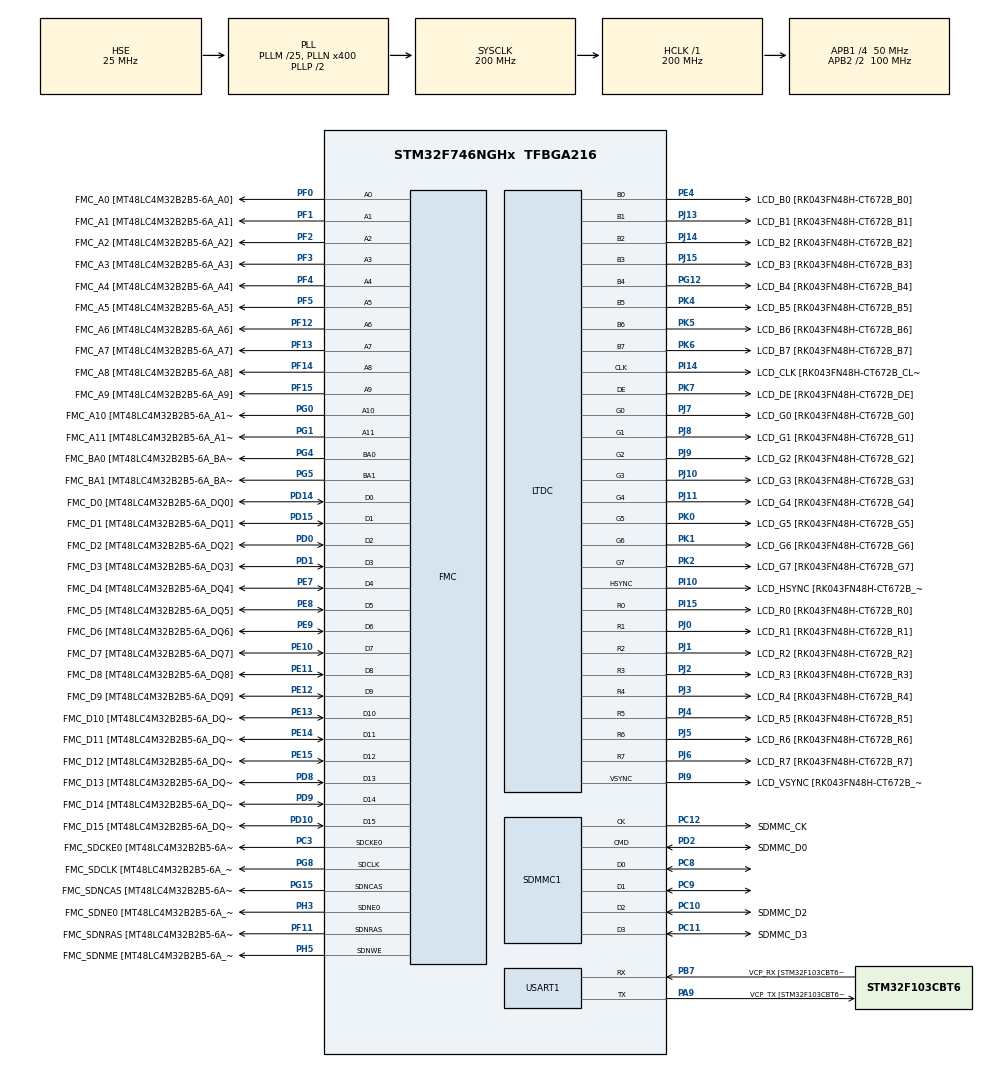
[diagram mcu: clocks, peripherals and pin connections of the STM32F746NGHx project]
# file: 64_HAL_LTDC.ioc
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CORTEX_M7.CPU_DCache=Enabled
CORTEX_M7.CPU_ICache=Enabled
FATFS._MAX_SS=4096
FMC.CASLatency1=FMC_SDRAM_CAS_LATENCY_2
FMC.ExitSelfRefreshDelay1=6
FMC.LoadToActiveDelay1=2
FMC.RCDDelay1=2
FMC.RPDelay1=2
FMC.RPDelay2=2
FMC.RowCycleDelay1=6
FMC.RowCycleDelay2=6
FMC.SelfRefreshTime1=4
FMC.WriteRecoveryTime1=2
FREERTOS.Tasks01=defaultTask,0,1280,StartDefaultTask,Default,NULL,Dynamic,NULL,NULL;myTask02,-3,128,StartTask02,Default,NULL,Dynamic,NULL,NULL;myTask03,-3,128,StartTask03,Default,NULL,Dynamic,NULL,NULL;myTask04,-3,128,StartTask04,Default,NULL,Dynamic,NULL,NULL;myTask05,-3,128,StartTask05,Default,NULL,Dynamic,NULL,NULL
FREERTOS.configUSE_IDLE_HOOK=0
LTDC.ActiveH=272
LTDC.ActiveW=480
LTDC.Alpha_L0=255
LTDC.Alpha_L1=255
LTDC.HBP=13
LTDC.HFP=32
LTDC.HSync=41
LTDC.Layers=0
LTDC.PixelFormat_L0=LTDC_PIXEL_FORMAT_RGB565
LTDC.VSync=10
LTDC.WindowX1_L0=480
LTDC.WindowX1_L1=480
LTDC.WindowY1_L0=272
LTDC.WindowY1_L1=272
Mcu.Family=STM32F7
Mcu.Name=STM32F746NGHx
Mcu.Package=TFBGA216
NVIC.PriorityGroup=NVIC_PRIORITYGROUP_4
NVIC.TIM1_UP_TIM10_IRQn=true\:15\:0\:false\:false\:true\:false\:false\:true
NVIC.TimeBase=TIM1_UP_TIM10_IRQn
NVIC.TimeBaseIP=TIM1
PA13.GPIO_Label=SWDIO
PA13.Mode=Serial_Wire
PA13.Signal=SYS_JTMS-SWDIO
PA14.GPIO_Label=SWCLK
PA14.Mode=Serial_Wire
PA14.Signal=SYS_JTCK-SWCLK
PA15.GPIO_Label=ARDUINO PWM/D9
PA15.GPIO_ModeDefaultPP=GPIO_MODE_AF_PP
PA15.GPIO_PuPd=GPIO_NOPULL
PA15.GPIO_Speed=GPIO_SPEED_FREQ_LOW
PA15.Signal=S_TIM2_CH1_ETR
PA9.GPIO_Label=VCP_TX [STM32F103CBT6_PA3]
PA9.GPIO_Mode=GPIO_MODE_AF_PP
PA9.GPIO_PuPd=GPIO_NOPULL
PA9.GPIO_Speed=GPIO_SPEED_FREQ_LOW
PA9.Mode=Asynchronous
PA9.Signal=USART1_TX
PB0.GPIO_Label=ULPI_D1 [USB3320C-EZK_D1]
PB0.Signal=USB_OTG_HS_ULPI_D1
PB1.GPIO_Label=ULPI_D2 [USB3320C-EZK_D2]
PB1.Signal=USB_OTG_HS_ULPI_D2
PB10.GPIO_Label=ULPI_D3 [USB3320C-EZK_D3]
PB10.Signal=USB_OTG_HS_ULPI_D3
PB11.GPIO_Label=ULPI_D4 [USB3320C-EZK_D4]
PB11.Signal=USB_OTG_HS_ULPI_D4
PB12.GPIO_Label=ULPI_D5 [USB3320C-EZK_D5]
PB12.Signal=USB_OTG_HS_ULPI_D5
PB13.GPIO_Label=ULPI_D6 [USB3320C-EZK_D6]
PB13.Signal=USB_OTG_HS_ULPI_D6
PB14.GPIO_Label=ARDUINO MISO/D12
PB14.GPIO_Mode=GPIO_MODE_AF_PP
PB14.GPIO_PuPd=GPIO_NOPULL
PB14.GPIO_Speed=GPIO_SPEED_FREQ_LOW
PB14.Signal=SPI2_MISO
PB15.GPIO_Label=ARDUINO MOSI/PWM/D11
PB15.GPIO_Mode=GPIO_MODE_AF_PP
PB15.GPIO_PuPd=GPIO_NOPULL
PB15.GPIO_Speed=GPIO_SPEED_FREQ_LOW
PB15.Signal=SPI2_MOSI
PB2.Signal=QUADSPI_CLK
PB3.GPIO_Label=SWO
PB3.Signal=SYS_JTDO-SWO
PB4.GPIO_Label=ARDUINO PWM/D3
PB4.GPIO_ModeDefaultPP=GPIO_MODE_AF_PP
PB4.GPIO_PuPd=GPIO_NOPULL
PB4.GPIO_Speed=GPIO_SPEED_FREQ_LOW
PB4.Signal=S_TIM3_CH1
PB5.GPIO_Label=ULPI_D7 [USB3320C-EZK_D7]
PB5.Signal=USB_OTG_HS_ULPI_D7
PB6.GPIO_Label=QSPI_NCS [N25Q128A13EF840E_S]
PB6.Signal=QUADSPI_BK1_NCS
PB7.GPIO_Label=VCP_RX [STM32F103CBT6_PA2]
PB7.GPIO_Mode=GPIO_MODE_AF_PP
PB7.GPIO_PuPd=GPIO_NOPULL
PB7.GPIO_Speed=GPIO_SPEED_FREQ_LOW
PB7.Mode=Asynchronous
PB7.Signal=USART1_RX
PB8.GPIO_Label=ARDUINO SCL/D15
PB8.GPIO_Mode=GPIO_MODE_AF_OD
PB8.GPIO_PuPd=GPIO_NOPULL
PB8.GPIO_Speed=GPIO_SPEED_FREQ_LOW
PB8.Signal=I2C1_SCL
PB9.GPIO_Label=ARDUINO SDA/D14
PB9.GPIO_Mode=GPIO_MODE_AF_OD
PB9.GPIO_PuPd=GPIO_NOPULL
PB9.GPIO_Speed=GPIO_SPEED_FREQ_LOW
PB9.Signal=I2C1_SDA
PC1.GPIO_Label=RMII_MDC [LAN8742A-CZ-TR_MDC]
PC1.Signal=ETH_MDC
PC10.GPIO_Label=SDMMC_D2
PC10.Mode=SD_4_bits_Wide_bus
PC10.Signal=SDMMC1_D2
PC11.GPIO_Label=SDMMC_D3
PC11.Mode=SD_4_bits_Wide_bus
PC11.Signal=SDMMC1_D3
PC12.GPIO_Label=SDMMC_CK
PC12.Mode=SD_4_bits_Wide_bus
PC12.Signal=SDMMC1_CK
PC14/OSC32_IN.GPIO_Label=RCC_OSC32_IN
PC14/OSC32_IN.Signal=RCC_OSC32_IN
PC15/OSC32_OUT.GPIO_Label=RCC_OSC32_OUT
PC15/OSC32_OUT.Signal=RCC_OSC32_OUT
PC2.GPIO_Label=ULPI_DIR [USB3320C-EZK_DIR]
PC2.Signal=USB_OTG_HS_ULPI_DIR
PC3.GPIO_Label=FMC_SDCKE0 [MT48LC4M32B2B5-6A_CKE]
PC3.Mode=SdramChipSelect1_1
PC3.Signal=FMC_SDCKE0
PC4.GPIO_Label=RMII_RXD0 [LAN8742A-CZ-TR_RXD0]
PC4.Signal=ETH_RXD0
PC5.GPIO_Label=RMII_RXD1 [LAN8742A-CZ-TR_RXD1]
PC5.Signal=ETH_RXD1
PC6.GPIO_Label=ARDUINO TX/D1
PC6.Signal=USART6_TX
PC7.GPIO_Label=ARDUINO RX/D0
PC7.Signal=USART6_RX
PC8.Mode=SD_4_bits_Wide_bus
PC8.Signal=SDMMC1_D0
PC9.Mode=SD_4_bits_Wide_bus
PC9.Signal=SDMMC1_D1
PD0.GPIO_Label=FMC_D2 [MT48LC4M32B2B5-6A_DQ2]
PD0.Signal=FMC_D2_DA2
PD1.GPIO_Label=FMC_D3 [MT48LC4M32B2B5-6A_DQ3]
PD1.Signal=FMC_D3_DA3
PD10.GPIO_Label=FMC_D15 [MT48LC4M32B2B5-6A_DQ15]
PD10.Signal=FMC_D15_DA15
PD11.GPIO_Label=QSPI_D0 [N25Q128A13EF840E_DQ0]
PD11.Signal=QUADSPI_BK1_IO0
PD12.GPIO_Label=QSPI_D1 [N25Q128A13EF840E_DQ1]
PD12.Signal=QUADSPI_BK1_IO1
PD13.GPIO_Label=QSPI_D3 [N25Q128A13EF840E_DQ3]
PD13.Signal=QUADSPI_BK1_IO3
PD14.GPIO_Label=FMC_D0 [MT48LC4M32B2B5-6A_DQ0]
PD14.Signal=FMC_D0_DA0
PD15.GPIO_Label=FMC_D1 [MT48LC4M32B2B5-6A_DQ1]
PD15.Signal=FMC_D1_DA1
PD2.GPIO_Label=SDMMC_D0
PD2.Mode=SD_4_bits_Wide_bus
PD2.Signal=SDMMC1_CMD
PD3.GPIO_Label=DCMI_D5
PD3.Signal=DCMI_D5
PD7.GPIO_Label=SPDIF_RX0 [74LVC1G04SE_4]
PD7.Signal=SPDIFRX_IN0
PD8.GPIO_Label=FMC_D13 [MT48LC4M32B2B5-6A_DQ13]
PD8.Signal=FMC_D13_DA13
PD9.GPIO_Label=FMC_D14 [MT48LC4M32B2B5-6A_DQ14]
PD9.Signal=FMC_D14_DA14
PE0.GPIO_Label=FMC_NBL0 [MT48LC4M32B2B5-6A_DQM0]
PE0.Signal=FMC_NBL0
PE1.GPIO_Label=FMC_NBL1 [MT48LC4M32B2B5-6A_DQM1]
PE1.Signal=FMC_NBL1
PE10.GPIO_Label=FMC_D7 [MT48LC4M32B2B5-6A_DQ7]
PE10.Signal=FMC_D7_DA7
PE11.GPIO_Label=FMC_D8 [MT48LC4M32B2B5-6A_DQ8]
PE11.Signal=FMC_D8_DA8
PE12.GPIO_Label=FMC_D9 [MT48LC4M32B2B5-6A_DQ9]
PE12.Signal=FMC_D9_DA9
PE13.GPIO_Label=FMC_D10 [MT48LC4M32B2B5-6A_DQ10]
PE13.Signal=FMC_D10_DA10
PE14.GPIO_Label=FMC_D11 [MT48LC4M32B2B5-6A_DQ11]
PE14.Signal=FMC_D11_DA11
PE15.GPIO_Label=FMC_D12 [MT48LC4M32B2B5-6A_DQ12]
PE15.Signal=FMC_D12_DA12
PE2.GPIO_Label=QSPI_D2 [N25Q128A13EF840E_DQ2]
PE2.Signal=QUADSPI_BK1_IO2
PE4.GPIO_Label=LCD_B0 [RK043FN48H-CT672B_B0]
PE4.Mode=RGB888
PE4.Signal=LTDC_B0
PE5.GPIO_Label=DCMI_D6
PE5.Signal=DCMI_D6
PE6.GPIO_Label=DCMI_D7
PE6.Signal=DCMI_D7
PE7.GPIO_Label=FMC_D4 [MT48LC4M32B2B5-6A_DQ4]
PE7.Signal=FMC_D4_DA4
PE8.GPIO_Label=FMC_D5 [MT48LC4M32B2B5-6A_DQ5]
PE8.Signal=FMC_D5_DA5
PE9.GPIO_Label=FMC_D6 [MT48LC4M32B2B5-6A_DQ6]
PE9.Signal=FMC_D6_DA6
PF0.GPIO_Label=FMC_A0 [MT48LC4M32B2B5-6A_A0]
PF0.Signal=FMC_A0
PF1.GPIO_Label=FMC_A1 [MT48LC4M32B2B5-6A_A1]
PF1.Signal=FMC_A1
PF10.GPIO_Label=ARDUINO A1
PF10.GPIO_Mode=GPIO_MODE_ANALOG
PF10.GPIO_PuPd=GPIO_NOPULL
PF10.Signal=ADC3_IN8
PF11.GPIO_Label=FMC_SDNRAS [MT48LC4M32B2B5-6A_RAS]
PF11.Signal=FMC_SDNRAS
PF12.GPIO_Label=FMC_A6 [MT48LC4M32B2B5-6A_A6]
PF12.Signal=FMC_A6
PF13.GPIO_Label=FMC_A7 [MT48LC4M32B2B5-6A_A7]
PF13.Signal=FMC_A7
PF14.GPIO_Label=FMC_A8 [MT48LC4M32B2B5-6A_A8]
PF14.Signal=FMC_A8
PF15.GPIO_Label=FMC_A9 [MT48LC4M32B2B5-6A_A9]
PF15.Signal=FMC_A9
PF2.GPIO_Label=FMC_A2 [MT48LC4M32B2B5-6A_A2]
PF2.Signal=FMC_A2
PF3.GPIO_Label=FMC_A3 [MT48LC4M32B2B5-6A_A3]
PF3.Signal=FMC_A3
PF4.GPIO_Label=FMC_A4 [MT48LC4M32B2B5-6A_A4]
PF4.Signal=FMC_A4
PF5.GPIO_Label=FMC_A5 [MT48LC4M32B2B5-6A_A5]
PF5.Signal=FMC_A5
PF6.GPIO_Label=ARDUINO A5
PF6.GPIO_Mode=GPIO_MODE_ANALOG
PF6.GPIO_PuPd=GPIO_NOPULL
PF6.Signal=ADC3_IN4
PF7.GPIO_Label=ARDUINO A4
PF7.GPIO_Mode=GPIO_MODE_ANALOG
PF7.GPIO_PuPd=GPIO_NOPULL
PF7.Signal=ADC3_IN5
PF8.GPIO_Label=ARDUINO A3
PF8.GPIO_Mode=GPIO_MODE_ANALOG
PF8.GPIO_PuPd=GPIO_NOPULL
PF8.Signal=ADC3_IN6
PF9.GPIO_Label=ARDUINO A2
PF9.GPIO_Mode=GPIO_MODE_ANALOG
PF9.GPIO_PuPd=GPIO_NOPULL
PF9.Signal=ADC3_IN7
PG0.GPIO_Label=FMC_A10 [MT48LC4M32B2B5-6A_A10]
PG0.Signal=FMC_A10
PG1.GPIO_Label=FMC_A11 [MT48LC4M32B2B5-6A_A11]
PG1.Signal=FMC_A11
PG10.GPIO_Label=SAI2_SDB [WM8994ECS/R_ADCDAT1]
PG10.Signal=SAI2_SD_B
PG11.GPIO_Label=RMII_TX_EN [LAN8742A-CZ-TR_TXEN]
PG11.Signal=ETH_TX_EN
PG12.GPIO_Label=LCD_B4 [RK043FN48H-CT672B_B4]
PG12.Mode=RGB888
PG12.Signal=LTDC_B4
PG13.GPIO_Label=RMII_TXD0 [LAN8742A-CZ-TR_TXD0]
PG13.Signal=ETH_TXD0
PG14.GPIO_Label=RMII_TXD1 [LAN8742A-CZ-TR_TXD1]
PG14.Signal=ETH_TXD1
PG15.GPIO_Label=FMC_SDNCAS [MT48LC4M32B2B5-6A_CAS]
PG15.Signal=FMC_SDNCAS
PG4.GPIO_Label=FMC_BA0 [MT48LC4M32B2B5-6A_BA0]
PG4.Signal=FMC_A14_BA0
PG5.GPIO_Label=FMC_BA1 [MT48LC4M32B2B5-6A_BA1]
PG5.Signal=FMC_A15_BA1
PG8.GPIO_Label=FMC_SDCLK [MT48LC4M32B2B5-6A_CLK]
PG8.Signal=FMC_SDCLK
PG9.GPIO_Label=DCMI_VSYNC
PG9.Signal=DCMI_VSYNC
PH0/OSC_IN.GPIO_Label=OSC_25M [NZ2520SB-25.00M_OUT]
PH0/OSC_IN.Mode=HSE-External-Oscillator
PH0/OSC_IN.Signal=RCC_OSC_IN
PH1/OSC_OUT.Mode=HSE-External-Oscillator
PH1/OSC_OUT.Signal=RCC_OSC_OUT
PH10.GPIO_Label=DCMI_D1
PH10.Signal=DCMI_D1
PH11.GPIO_Label=DCMI_D2
PH11.Signal=DCMI_D2
PH12.GPIO_Label=DCMI_D3
PH12.Signal=DCMI_D3
PH14.GPIO_Label=DCMI_D4
PH14.Signal=DCMI_D4
PH3.GPIO_Label=FMC_SDNE0 [MT48LC4M32B2B5-6A_CS]
PH3.Mode=SdramChipSelect1_1
PH3.Signal=FMC_SDNE0
PH4.GPIO_Label=ULPI_NXT [USB3320C-EZK_NXT]
PH4.Signal=USB_OTG_HS_ULPI_NXT
PH5.GPIO_Label=FMC_SDNME [MT48LC4M32B2B5-6A_WE]
PH5.Signal=FMC_SDNWE
PH6.GPIO_Label=ARDUINO PWM/D6
PH6.Signal=S_TIM12_CH1
PH7.GPIO_Label=LCD_SCL [RK043FN48H-CT672B_SCL]
PH7.Signal=I2C3_SCL
PH8.GPIO_Label=LCD_SDA [RK043FN48H-CT672B_SDA]
PH8.Signal=I2C3_SDA
PH9.GPIO_Label=DCMI_D0
PH9.Signal=DCMI_D0
PI0.GPIO_Label=ARDUINO PWM/CS/D5
PI0.GPIO_ModeDefaultPP=GPIO_MODE_AF_PP
PI0.GPIO_PuPd=GPIO_NOPULL
PI0.GPIO_Speed=GPIO_SPEED_FREQ_LOW
PI0.Signal=S_TIM5_CH4
PI1.GPIO_Label=ARDUINO SCK/D13
PI1.GPIO_Mode=GPIO_MODE_AF_PP
PI1.GPIO_PuPd=GPIO_NOPULL
PI1.GPIO_Speed=GPIO_SPEED_FREQ_LOW
PI1.Signal=SPI2_SCK
PI10.GPIO_Label=LCD_HSYNC [RK043FN48H-CT672B_HSYNC]
PI10.Mode=RGB888
PI10.Signal=LTDC_HSYNC
PI14.GPIO_Label=LCD_CLK [RK043FN48H-CT672B_CLK]
PI14.Mode=RGB888
PI14.Signal=LTDC_CLK
PI15.GPIO_Label=LCD_R0 [RK043FN48H-CT672B_R0]
PI15.Mode=RGB888
PI15.Signal=LTDC_R0
PI4.GPIO_Label=SAI2_MCLKA [WM8994ECS/R_MCLK1]
PI4.Signal=SAI2_MCLK_A
PI5.GPIO_Label=SAI2_SCKA [WM8994ECS/R_BCLK1]
PI5.Signal=SAI2_SCK_A
PI6.GPIO_Label=SAI2_SDA [WM8994ECS/R_DACDAT1]
PI6.Signal=SAI2_SD_A
PI7.GPIO_Label=SAI2_FSA [WM8994ECS/R_LRCLK1]
PI7.Signal=SAI2_FS_A
PI9.GPIO_Label=LCD_VSYNC [RK043FN48H-CT672B_VSYNC]
PI9.Mode=RGB888
PI9.Signal=LTDC_VSYNC
PJ0.GPIO_Label=LCD_R1 [RK043FN48H-CT672B_R1]
PJ0.Mode=RGB888
PJ0.Signal=LTDC_R1
PJ1.GPIO_Label=LCD_R2 [RK043FN48H-CT672B_R2]
PJ1.Mode=RGB888
PJ1.Signal=LTDC_R2
PJ10.GPIO_Label=LCD_G3 [RK043FN48H-CT672B_G3]
PJ10.Mode=RGB888
PJ10.Signal=LTDC_G3
PJ11.GPIO_Label=LCD_G4 [RK043FN48H-CT672B_G4]
PJ11.Mode=RGB888
PJ11.Signal=LTDC_G4
PJ13.GPIO_Label=LCD_B1 [RK043FN48H-CT672B_B1]
PJ13.Mode=RGB888
PJ13.Signal=LTDC_B1
PJ14.GPIO_Label=LCD_B2 [RK043FN48H-CT672B_B2]
PJ14.Mode=RGB888
PJ14.Signal=LTDC_B2
PJ15.GPIO_Label=LCD_B3 [RK043FN48H-CT672B_B3]
PJ15.Mode=RGB888
PJ15.Signal=LTDC_B3
PJ2.GPIO_Label=LCD_R3 [RK043FN48H-CT672B_R3]
PJ2.Mode=RGB888
PJ2.Signal=LTDC_R3
PJ3.GPIO_Label=LCD_R4 [RK043FN48H-CT672B_R4]
PJ3.Mode=RGB888
PJ3.Signal=LTDC_R4
PJ4.GPIO_Label=LCD_R5 [RK043FN48H-CT672B_R5]
PJ4.Mode=RGB888
PJ4.Signal=LTDC_R5
PJ5.GPIO_Label=LCD_R6 [RK043FN48H-CT672B_R6]
PJ5.Mode=RGB888
PJ5.Signal=LTDC_R6
PJ6.GPIO_Label=LCD_R7 [RK043FN48H-CT672B_R7]
PJ6.Mode=RGB888
PJ6.Signal=LTDC_R7
PJ7.GPIO_Label=LCD_G0 [RK043FN48H-CT672B_G0]
PJ7.Mode=RGB888
PJ7.Signal=LTDC_G0
PJ8.GPIO_Label=LCD_G1 [RK043FN48H-CT672B_G1]
PJ8.Mode=RGB888
PJ8.Signal=LTDC_G1
PJ9.GPIO_Label=LCD_G2 [RK043FN48H-CT672B_G2]
PJ9.Mode=RGB888
PJ9.Signal=LTDC_G2
PK0.GPIO_Label=LCD_G5 [RK043FN48H-CT672B_G5]
PK0.Mode=RGB888
PK0.Signal=LTDC_G5
PK1.GPIO_Label=LCD_G6 [RK043FN48H-CT672B_G6]
PK1.Mode=RGB888
PK1.Signal=LTDC_G6
PK2.GPIO_Label=LCD_G7 [RK043FN48H-CT672B_G7]
PK2.Mode=RGB888
PK2.Signal=LTDC_G7
PK4.GPIO_Label=LCD_B5 [RK043FN48H-CT672B_B5]
PK4.Mode=RGB888
PK4.Signal=LTDC_B5
PK5.GPIO_Label=LCD_B6 [RK043FN48H-CT672B_B6]
PK5.Mode=RGB888
PK5.Signal=LTDC_B6
PK6.GPIO_Label=LCD_B7 [RK043FN48H-CT672B_B7]
PK6.Mode=RGB888
PK6.Signal=LTDC_B7
PK7.GPIO_Label=LCD_DE [RK043FN48H-CT672B_DE]
PK7.Mode=RGB888
PK7.Signal=LTDC_DE
ProjectManager.HeapSize=0x200
ProjectManager.StackSize=0x400
ProjectManager.TargetToolchain=STM32CubeIDE
RCC.AHBFreq_Value=200000000
RCC.APB1CLKDivider=RCC_HCLK_DIV4
RCC.APB1Freq_Value=50000000
RCC.APB1TimFreq_Value=100000000
RCC.APB2CLKDivider=RCC_HCLK_DIV2
RCC.APB2Freq_Value=100000000
RCC.APB2TimFreq_Value=200000000
RCC.CortexFreq_Value=200000000
RCC.HCLKFreq_Value=200000000
RCC.HSE_VALUE=25000000
RCC.HSI_VALUE=16000000
RCC.LSE_VALUE=32768
RCC.PLL48CLockSelection=RCC_CLK48SOURCE_PLLSAIP
RCC.PLLM=25
RCC.PLLN=400
RCC.PLLQ=8
RCC.PLLSAIP=RCC_PLLSAIP_DIV4
RCC.PLLSAIRDiv=RCC_PLLSAIDIVR_4
RCC.PLLSourceVirtual=RCC_PLLSOURCE_HSE
RCC.SDMMCClockSelection=RCC_SDMMC1CLKSOURCE_CLK48
RCC.SYSCLKFreq_VALUE=200000000
RCC.SYSCLKSource=RCC_SYSCLKSOURCE_PLLCLK
RCC.USBFreq_Value=48000000
RCC.VCOOutputFreq_Value=400000000
SH.FMC_A0.0=FMC_A0,12b-sda1
SH.FMC_A1.0=FMC_A1,12b-sda1
SH.FMC_A10.0=FMC_A10,12b-sda1
SH.FMC_A11.0=FMC_A11,12b-sda1
SH.FMC_A14_BA0.0=FMC_BA0,FourSdramBanks1
SH.FMC_A15_BA1.0=FMC_BA1,FourSdramBanks1
SH.FMC_A2.0=FMC_A2,12b-sda1
SH.FMC_A3.0=FMC_A3,12b-sda1
SH.FMC_A4.0=FMC_A4,12b-sda1
SH.FMC_A5.0=FMC_A5,12b-sda1
SH.FMC_A6.0=FMC_A6,12b-sda1
SH.FMC_A7.0=FMC_A7,12b-sda1
SH.FMC_A8.0=FMC_A8,12b-sda1
SH.FMC_A9.0=FMC_A9,12b-sda1
SH.FMC_D0_DA0.0=FMC_D0,sd-16b-d1
SH.FMC_D10_DA10.0=FMC_D10,sd-16b-d1
SH.FMC_D11_DA11.0=FMC_D11,sd-16b-d1
SH.FMC_D12_DA12.0=FMC_D12,sd-16b-d1
SH.FMC_D13_DA13.0=FMC_D13,sd-16b-d1
SH.FMC_D14_DA14.0=FMC_D14,sd-16b-d1
SH.FMC_D15_DA15.0=FMC_D15,sd-16b-d1
SH.FMC_D1_DA1.0=FMC_D1,sd-16b-d1
SH.FMC_D2_DA2.0=FMC_D2,sd-16b-d1
SH.FMC_D3_DA3.0=FMC_D3,sd-16b-d1
SH.FMC_D4_DA4.0=FMC_D4,sd-16b-d1
SH.FMC_D5_DA5.0=FMC_D5,sd-16b-d1
SH.FMC_D6_DA6.0=FMC_D6,sd-16b-d1
SH.FMC_D7_DA7.0=FMC_D7,sd-16b-d1
SH.FMC_D8_DA8.0=FMC_D8,sd-16b-d1
SH.FMC_D9_DA9.0=FMC_D9,sd-16b-d1
SH.FMC_NBL0.0=FMC_NBL0
SH.FMC_NBL1.0=FMC_NBL1
SH.FMC_SDCLK.0=FMC_SDCLK,12b-sda1
SH.FMC_SDNCAS.0=FMC_SDNCAS,12b-sda1
SH.FMC_SDNRAS.0=FMC_SDNRAS,12b-sda1
SH.FMC_SDNWE.0=FMC_SDNWE,12b-sda1
SH.S_TIM12_CH1.0=TIM12_CH1
SH.S_TIM2_CH1_ETR.0=TIM2_CH1
SH.S_TIM3_CH1.0=TIM3_CH1
SH.S_TIM5_CH4.0=TIM5_CH4
USART1.VirtualMode-Asynchronous=VM_ASYNC
VP_DMA2D_VS_DMA2D.Mode=DMA2D_Activate
VP_FATFS_VS_SDIO.Mode=SDIO
VP_FREERTOS_VS_CMSIS_V1.Mode=CMSIS_V1
VP_RNG_VS_RNG.Mode=RNG_Activate
VP_SYS_VS_tim1.Mode=TIM1
board=STM32F746G-DISCO

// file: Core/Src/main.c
/* USER CODE BEGIN Header */
/**
  ******************************************************************************
  * @file           : main.c
  * @brief          : Main program body
  ******************************************************************************
  * @attention
  *
  * Copyright (c) 2022 STMicroelectronics.
  * All rights reserved.
  *
  * This software is licensed under terms that can be found in the LICENSE file
  * in the root directory of this software component.
  * If no LICENSE file comes with this software, it is provided AS-IS.
  *
  ******************************************************************************
  */
/* USER CODE END Header */
#include "main.h"
#include "cmsis_os.h"
#include "fatfs.h"

DMA2D_HandleTypeDef hdma2d;

LTDC_HandleTypeDef hltdc;

RNG_HandleTypeDef hrng;

SD_HandleTypeDef hsd1;

UART_HandleTypeDef huart1;

SDRAM_HandleTypeDef hsdram1;

osThreadId defaultTaskHandle;
osThreadId myTask02Handle;
osThreadId myTask03Handle;
osThreadId myTask04Handle;
osThreadId myTask05Handle;

void SystemClock_Config(void);
void PeriphCommonClock_Config(void);
static void MX_GPIO_Init(void);
static void MX_DMA2D_Init(void);
static void MX_FMC_Init(void);
static void MX_LTDC_Init(void);
static void MX_USART1_UART_Init(void);
static void MX_SDMMC1_SD_Init(void);
static void MX_RNG_Init(void);
void StartDefaultTask(void const * argument);
void StartTask02(void const * argument);
void StartTask03(void const * argument);
void StartTask04(void const * argument);
void StartTask05(void const * argument);

int main(void)
{

  /* Enable I-Cache---------------------------------------------------------*/
  SCB_EnableICache();

  /* Enable D-Cache---------------------------------------------------------*/
  SCB_EnableDCache();

  /* MCU Configuration--------------------------------------------------------*/

  /* Reset of all peripherals, Initializes the Flash interface and the Systick. */
  HAL_Init();

  /* Configure the system clock */
  SystemClock_Config();

/* Configure the peripherals common clocks */
  PeriphCommonClock_Config();

  /* Initialize all configured peripherals */
  MX_GPIO_Init();
  MX_DMA2D_Init();
  MX_FMC_Init();
  MX_LTDC_Init();
  MX_USART1_UART_Init();
  MX_SDMMC1_SD_Init();
  MX_FATFS_Init();
  MX_RNG_Init();

  /* Create the thread(s) */
  /* definition and creation of defaultTask */
  osThreadDef(defaultTask, StartDefaultTask, osPriorityNormal, 0, 1280);
  defaultTaskHandle = osThreadCreate(osThread(defaultTask), NULL);

  /* definition and creation of myTask02 */
  osThreadDef(myTask02, StartTask02, osPriorityIdle, 0, 128);
  myTask02Handle = osThreadCreate(osThread(myTask02), NULL);

  /* definition and creation of myTask03 */
  osThreadDef(myTask03, StartTask03, osPriorityIdle, 0, 128);
  myTask03Handle = osThreadCreate(osThread(myTask03), NULL);

  /* definition and creation of myTask04 */
  osThreadDef(myTask04, StartTask04, osPriorityIdle, 0, 128);
  myTask04Handle = osThreadCreate(osThread(myTask04), NULL);

  /* definition and creation of myTask05 */
  osThreadDef(myTask05, StartTask05, osPriorityIdle, 0, 128);
  myTask05Handle = osThreadCreate(osThread(myTask05), NULL);

  /* Start scheduler */
  osKernelStart();

  /* We should never get here as control is now taken by the scheduler */
  /* Infinite loop */
  while (1)
  {

  }
}

void SystemClock_Config(void)
{
  RCC_OscInitTypeDef RCC_OscInitStruct = {0};
  RCC_ClkInitTypeDef RCC_ClkInitStruct = {0};

  /** Configure the main internal regulator output voltage
  */
  __HAL_RCC_PWR_CLK_ENABLE();
  __HAL_PWR_VOLTAGESCALING_CONFIG(PWR_REGULATOR_VOLTAGE_SCALE1);
  /** Initializes the RCC Oscillators according to the specified parameters
  * in the RCC_OscInitTypeDef structure.
  */
  RCC_OscInitStruct.OscillatorType = RCC_OSCILLATORTYPE_HSE;
  RCC_OscInitStruct.HSEState = RCC_HSE_ON;
  RCC_OscInitStruct.PLL.PLLState = RCC_PLL_ON;
  RCC_OscInitStruct.PLL.PLLSource = RCC_PLLSOURCE_HSE;
  RCC_OscInitStruct.PLL.PLLM = 25;
  RCC_OscInitStruct.PLL.PLLN = 400;
  RCC_OscInitStruct.PLL.PLLP = RCC_PLLP_DIV2;
  RCC_OscInitStruct.PLL.PLLQ = 8;
  if (HAL_RCC_OscConfig(&RCC_OscInitStruct) != HAL_OK)
  {
    Error_Handler();
  }
  /** Activate the Over-Drive mode
  */
  if (HAL_PWREx_EnableOverDrive() != HAL_OK)
  {
    Error_Handler();
  }
  /** Initializes the CPU, AHB and APB buses clocks
  */
  RCC_ClkInitStruct.ClockType = RCC_CLOCKTYPE_HCLK|RCC_CLOCKTYPE_SYSCLK
                              |RCC_CLOCKTYPE_PCLK1|RCC_CLOCKTYPE_PCLK2;
  RCC_ClkInitStruct.SYSCLKSource = RCC_SYSCLKSOURCE_PLLCLK;
  RCC_ClkInitStruct.AHBCLKDivider = RCC_SYSCLK_DIV1;
  RCC_ClkInitStruct.APB1CLKDivider = RCC_HCLK_DIV4;
  RCC_ClkInitStruct.APB2CLKDivider = RCC_HCLK_DIV2;

  if (HAL_RCC_ClockConfig(&RCC_ClkInitStruct, FLASH_LATENCY_6) != HAL_OK)
  {
    Error_Handler();
  }
}

void PeriphCommonClock_Config(void)
{
  RCC_PeriphCLKInitTypeDef PeriphClkInitStruct = {0};

  /** Initializes the peripherals clock
  */
  PeriphClkInitStruct.PeriphClockSelection = RCC_PERIPHCLK_LTDC|RCC_PERIPHCLK_SDMMC1
                              |RCC_PERIPHCLK_CLK48;
  PeriphClkInitStruct.PLLSAI.PLLSAIN = 192;
  PeriphClkInitStruct.PLLSAI.PLLSAIR = 2;
  PeriphClkInitStruct.PLLSAI.PLLSAIQ = 2;
  PeriphClkInitStruct.PLLSAI.PLLSAIP = RCC_PLLSAIP_DIV4;
  PeriphClkInitStruct.PLLSAIDivQ = 1;
  PeriphClkInitStruct.PLLSAIDivR = RCC_PLLSAIDIVR_4;
  PeriphClkInitStruct.Clk48ClockSelection = RCC_CLK48SOURCE_PLLSAIP;
  PeriphClkInitStruct.Sdmmc1ClockSelection = RCC_SDMMC1CLKSOURCE_CLK48;
  if (HAL_RCCEx_PeriphCLKConfig(&PeriphClkInitStruct) != HAL_OK)
  {
    Error_Handler();
  }
}

static void MX_DMA2D_Init(void)
{

  hdma2d.Instance = DMA2D;
  hdma2d.Init.Mode = DMA2D_M2M;
  hdma2d.Init.ColorMode = DMA2D_OUTPUT_ARGB8888;
  hdma2d.Init.OutputOffset = 0;
  hdma2d.LayerCfg[1].InputOffset = 0;
  hdma2d.LayerCfg[1].InputColorMode = DMA2D_INPUT_ARGB8888;
  hdma2d.LayerCfg[1].AlphaMode = DMA2D_NO_MODIF_ALPHA;
  hdma2d.LayerCfg[1].InputAlpha = 0;
  if (HAL_DMA2D_Init(&hdma2d) != HAL_OK)
  {
    Error_Handler();
  }
  if (HAL_DMA2D_ConfigLayer(&hdma2d, 1) != HAL_OK)
  {
    Error_Handler();
  }

}

static void MX_LTDC_Init(void)
{

  LTDC_LayerCfgTypeDef pLayerCfg = {0};

  hltdc.Instance = LTDC;
  hltdc.Init.HSPolarity = LTDC_HSPOLARITY_AL;
  hltdc.Init.VSPolarity = LTDC_VSPOLARITY_AL;
  hltdc.Init.DEPolarity = LTDC_DEPOLARITY_AL;
  hltdc.Init.PCPolarity = LTDC_PCPOLARITY_IPC;
  hltdc.Init.HorizontalSync = 40;
  hltdc.Init.VerticalSync = 9;
  hltdc.Init.AccumulatedHBP = 53;
  hltdc.Init.AccumulatedVBP = 11;
  hltdc.Init.AccumulatedActiveW = 533;
  hltdc.Init.AccumulatedActiveH = 283;
  hltdc.Init.TotalWidth = 565;
  hltdc.Init.TotalHeigh = 285;
  hltdc.Init.Backcolor.Blue = 0;
  hltdc.Init.Backcolor.Green = 0;
  hltdc.Init.Backcolor.Red = 0;
  if (HAL_LTDC_Init(&hltdc) != HAL_OK)
  {
    Error_Handler();
  }
  pLayerCfg.WindowX0 = 0;
  pLayerCfg.WindowX1 = 480;
  pLayerCfg.WindowY0 = 0;
  pLayerCfg.WindowY1 = 272;
  pLayerCfg.PixelFormat = LTDC_PIXEL_FORMAT_RGB565;
  pLayerCfg.Alpha = 255;
  pLayerCfg.Alpha0 = 0;
  pLayerCfg.BlendingFactor1 = LTDC_BLENDING_FACTOR1_CA;
  pLayerCfg.BlendingFactor2 = LTDC_BLENDING_FACTOR2_CA;
  pLayerCfg.FBStartAdress = 0;
  pLayerCfg.ImageWidth = 0;
  pLayerCfg.ImageHeight = 0;
  pLayerCfg.Backcolor.Blue = 0;
  pLayerCfg.Backcolor.Green = 0;
  pLayerCfg.Backcolor.Red = 0;
  if (HAL_LTDC_ConfigLayer(&hltdc, &pLayerCfg, 0) != HAL_OK)
  {
    Error_Handler();
  }

}

static void MX_RNG_Init(void)
{

  hrng.Instance = RNG;
  if (HAL_RNG_Init(&hrng) != HAL_OK)
  {
    Error_Handler();
  }

}

static void MX_SDMMC1_SD_Init(void)
{

  hsd1.Instance = SDMMC1;
  hsd1.Init.ClockEdge = SDMMC_CLOCK_EDGE_RISING;
  hsd1.Init.ClockBypass = SDMMC_CLOCK_BYPASS_DISABLE;
  hsd1.Init.ClockPowerSave = SDMMC_CLOCK_POWER_SAVE_DISABLE;
  hsd1.Init.BusWide = SDMMC_BUS_WIDE_1B;
  hsd1.Init.HardwareFlowControl = SDMMC_HARDWARE_FLOW_CONTROL_DISABLE;
  hsd1.Init.ClockDiv = 0;

}

static void MX_USART1_UART_Init(void)
{

  huart1.Instance = USART1;
  huart1.Init.BaudRate = 115200;
  huart1.Init.WordLength = UART_WORDLENGTH_8B;
  huart1.Init.StopBits = UART_STOPBITS_1;
  huart1.Init.Parity = UART_PARITY_NONE;
  huart1.Init.Mode = UART_MODE_TX_RX;
  huart1.Init.HwFlowCtl = UART_HWCONTROL_NONE;
  huart1.Init.OverSampling = UART_OVERSAMPLING_16;
  huart1.Init.OneBitSampling = UART_ONE_BIT_SAMPLE_DISABLE;
  huart1.AdvancedInit.AdvFeatureInit = UART_ADVFEATURE_NO_INIT;
  if (HAL_UART_Init(&huart1) != HAL_OK)
  {
    Error_Handler();
  }

}

/* FMC initialization function */
static void MX_FMC_Init(void)
{

  FMC_SDRAM_TimingTypeDef SdramTiming = {0};

  /** Perform the SDRAM1 memory initialization sequence
  */
  hsdram1.Instance = FMC_SDRAM_DEVICE;
  /* hsdram1.Init */
  hsdram1.Init.SDBank = FMC_SDRAM_BANK1;
  hsdram1.Init.ColumnBitsNumber = FMC_SDRAM_COLUMN_BITS_NUM_8;
  hsdram1.Init.RowBitsNumber = FMC_SDRAM_ROW_BITS_NUM_12;
  hsdram1.Init.MemoryDataWidth = FMC_SDRAM_MEM_BUS_WIDTH_16;
  hsdram1.Init.InternalBankNumber = FMC_SDRAM_INTERN_BANKS_NUM_4;
  hsdram1.Init.CASLatency = FMC_SDRAM_CAS_LATENCY_2;
  hsdram1.Init.WriteProtection = FMC_SDRAM_WRITE_PROTECTION_DISABLE;
  hsdram1.Init.SDClockPeriod = FMC_SDRAM_CLOCK_DISABLE;
  hsdram1.Init.ReadBurst = FMC_SDRAM_RBURST_DISABLE;
  hsdram1.Init.ReadPipeDelay = FMC_SDRAM_RPIPE_DELAY_0;
  /* SdramTiming */
  SdramTiming.LoadToActiveDelay = 2;
  SdramTiming.ExitSelfRefreshDelay = 6;
  SdramTiming.SelfRefreshTime = 4;
  SdramTiming.RowCycleDelay = 6;
  SdramTiming.WriteRecoveryTime = 2;
  SdramTiming.RPDelay = 2;
  SdramTiming.RCDDelay = 2;

  if (HAL_SDRAM_Init(&hsdram1, &SdramTiming) != HAL_OK)
  {
    Error_Handler( );
  }

}

static void MX_GPIO_Init(void)
{
  GPIO_InitTypeDef GPIO_InitStruct = {0};

  /* GPIO Ports Clock Enable */
  __HAL_RCC_GPIOE_CLK_ENABLE();
  __HAL_RCC_GPIOG_CLK_ENABLE();
  __HAL_RCC_GPIOB_CLK_ENABLE();
  __HAL_RCC_GPIOD_CLK_ENABLE();
  __HAL_RCC_GPIOC_CLK_ENABLE();
  __HAL_RCC_GPIOA_CLK_ENABLE();
  __HAL_RCC_GPIOJ_CLK_ENABLE();
  __HAL_RCC_GPIOI_CLK_ENABLE();
  __HAL_RCC_GPIOK_CLK_ENABLE();
  __HAL_RCC_GPIOF_CLK_ENABLE();
  __HAL_RCC_GPIOH_CLK_ENABLE();

  /*Configure GPIO pin Output Level */
  HAL_GPIO_WritePin(OTG_FS_PowerSwitchOn_GPIO_Port, OTG_FS_PowerSwitchOn_Pin, GPIO_PIN_SET);

  /*Configure GPIO pin Output Level */
  HAL_GPIO_WritePin(GPIOI, ARDUINO_D7_Pin|ARDUINO_D8_Pin|LCD_DISP_Pin, GPIO_PIN_RESET);

  /*Configure GPIO pin Output Level */
  HAL_GPIO_WritePin(LCD_BL_CTRL_GPIO_Port, LCD_BL_CTRL_Pin, GPIO_PIN_RESET);

  /*Configure GPIO pin Output Level */
  HAL_GPIO_WritePin(DCMI_PWR_EN_GPIO_Port, DCMI_PWR_EN_Pin, GPIO_PIN_RESET);

  /*Configure GPIO pin Output Level */
  HAL_GPIO_WritePin(GPIOG, ARDUINO_D4_Pin|ARDUINO_D2_Pin|EXT_RST_Pin, GPIO_PIN_RESET);

  /*Configure GPIO pin : OTG_HS_OverCurrent_Pin */
  GPIO_InitStruct.Pin = OTG_HS_OverCurrent_Pin;
  GPIO_InitStruct.Mode = GPIO_MODE_INPUT;
  GPIO_InitStruct.Pull = GPIO_NOPULL;
  HAL_GPIO_Init(OTG_HS_OverCurrent_GPIO_Port, &GPIO_InitStruct);

  /*Configure GPIO pin : QSPI_D2_Pin */
  GPIO_InitStruct.Pin = QSPI_D2_Pin;
  GPIO_InitStruct.Mode = GPIO_MODE_AF_PP;
  GPIO_InitStruct.Pull = GPIO_NOPULL;
  GPIO_InitStruct.Speed = GPIO_SPEED_FREQ_VERY_HIGH;
  GPIO_InitStruct.Alternate = GPIO_AF9_QUADSPI;
  HAL_GPIO_Init(QSPI_D2_GPIO_Port, &GPIO_InitStruct);

  /*Configure GPIO pins : RMII_TXD1_Pin RMII_TXD0_Pin RMII_TX_EN_Pin */
  GPIO_InitStruct.Pin = RMII_TXD1_Pin|RMII_TXD0_Pin|RMII_TX_EN_Pin;
  GPIO_InitStruct.Mode = GPIO_MODE_AF_PP;
  GPIO_InitStruct.Pull = GPIO_NOPULL;
  GPIO_InitStruct.Speed = GPIO_SPEED_FREQ_VERY_HIGH;
  GPIO_InitStruct.Alternate = GPIO_AF11_ETH;
  HAL_GPIO_Init(GPIOG, &GPIO_InitStruct);

  /*Configure GPIO pins : ARDUINO_SCL_D15_Pin ARDUINO_SDA_D14_Pin */
  GPIO_InitStruct.Pin = ARDUINO_SCL_D15_Pin|ARDUINO_SDA_D14_Pin;
  GPIO_InitStruct.Mode = GPIO_MODE_AF_OD;
  GPIO_InitStruct.Pull = GPIO_NOPULL;
  GPIO_InitStruct.Speed = GPIO_SPEED_FREQ_LOW;
  GPIO_InitStruct.Alternate = GPIO_AF4_I2C1;
  HAL_GPIO_Init(GPIOB, &GPIO_InitStruct);

  /*Configure GPIO pins : ULPI_D7_Pin ULPI_D6_Pin ULPI_D5_Pin ULPI_D3_Pin
                           ULPI_D2_Pin ULPI_D1_Pin ULPI_D4_Pin */
  GPIO_InitStruct.Pin = ULPI_D7_Pin|ULPI_D6_Pin|ULPI_D5_Pin|ULPI_D3_Pin
                          |ULPI_D2_Pin|ULPI_D1_Pin|ULPI_D4_Pin;
  GPIO_InitStruct.Mode = GPIO_MODE_AF_PP;
  GPIO_InitStruct.Pull = GPIO_NOPULL;
  GPIO_InitStruct.Speed = GPIO_SPEED_FREQ_VERY_HIGH;
  GPIO_InitStruct.Alternate = GPIO_AF10_OTG_HS;
  HAL_GPIO_Init(GPIOB, &GPIO_InitStruct);

  /*Configure GPIO pin : ARDUINO_PWM_D3_Pin */
  GPIO_InitStruct.Pin = ARDUINO_PWM_D3_Pin;
  GPIO_InitStruct.Mode = GPIO_MODE_AF_PP;
  GPIO_InitStruct.Pull = GPIO_NOPULL;
  GPIO_InitStruct.Speed = GPIO_SPEED_FREQ_LOW;
  GPIO_InitStruct.Alternate = GPIO_AF2_TIM3;
  HAL_GPIO_Init(ARDUINO_PWM_D3_GPIO_Port, &GPIO_InitStruct);

  /*Configure GPIO pin : SPDIF_RX0_Pin */
  GPIO_InitStruct.Pin = SPDIF_RX0_Pin;
  GPIO_InitStruct.Mode = GPIO_MODE_AF_PP;
  GPIO_InitStruct.Pull = GPIO_NOPULL;
  GPIO_InitStruct.Speed = GPIO_SPEED_FREQ_LOW;
  GPIO_InitStruct.Alternate = GPIO_AF8_SPDIFRX;
  HAL_GPIO_Init(SPDIF_RX0_GPIO_Port, &GPIO_InitStruct);

  /*Configure GPIO pin : ARDUINO_PWM_D9_Pin */
  GPIO_InitStruct.Pin = ARDUINO_PWM_D9_Pin;
  GPIO_InitStruct.Mode = GPIO_MODE_AF_PP;
  GPIO_InitStruct.Pull = GPIO_NOPULL;
  GPIO_InitStruct.Speed = GPIO_SPEED_FREQ_LOW;
  GPIO_InitStruct.Alternate = GPIO_AF1_TIM2;
  HAL_GPIO_Init(ARDUINO_PWM_D9_GPIO_Port, &GPIO_InitStruct);

  /*Configure GPIO pins : DCMI_D6_Pin DCMI_D7_Pin */
  GPIO_InitStruct.Pin = DCMI_D6_Pin|DCMI_D7_Pin;
  GPIO_InitStruct.Mode = GPIO_MODE_AF_PP;
  GPIO_InitStruct.Pull = GPIO_NOPULL;
  GPIO_InitStruct.Speed = GPIO_SPEED_FREQ_LOW;
  GPIO_InitStruct.Alternate = GPIO_AF13_DCMI;
  HAL_GPIO_Init(GPIOE, &GPIO_InitStruct);

  /*Configure GPIO pin : QSPI_NCS_Pin */
  GPIO_InitStruct.Pin = QSPI_NCS_Pin;
  GPIO_InitStruct.Mode = GPIO_MODE_AF_PP;
  GPIO_InitStruct.Pull = GPIO_NOPULL;
  GPIO_InitStruct.Speed = GPIO_SPEED_FREQ_VERY_HIGH;
  GPIO_InitStruct.Alternate = GPIO_AF10_QUADSPI;
  HAL_GPIO_Init(QSPI_NCS_GPIO_Port, &GPIO_InitStruct);

  /*Configure GPIO pin : OTG_FS_VBUS_Pin */
  GPIO_InitStruct.Pin = OTG_FS_VBUS_Pin;
  GPIO_InitStruct.Mode = GPIO_MODE_INPUT;
  GPIO_InitStruct.Pull = GPIO_NOPULL;
  HAL_GPIO_Init(OTG_FS_VBUS_GPIO_Port, &GPIO_InitStruct);

  /*Configure GPIO pin : Audio_INT_Pin */
  GPIO_InitStruct.Pin = Audio_INT_Pin;
  GPIO_InitStruct.Mode = GPIO_MODE_EVT_RISING;
  GPIO_InitStruct.Pull = GPIO_NOPULL;
  HAL_GPIO_Init(Audio_INT_GPIO_Port, &GPIO_InitStruct);

  /*Configure GPIO pins : OTG_FS_P_Pin OTG_FS_N_Pin OTG_FS_ID_Pin */
  GPIO_InitStruct.Pin = OTG_FS_P_Pin|OTG_FS_N_Pin|OTG_FS_ID_Pin;
  GPIO_InitStruct.Mode = GPIO_MODE_AF_PP;
  GPIO_InitStruct.Pull = GPIO_NOPULL;
  GPIO_InitStruct.Speed = GPIO_SPEED_FREQ_VERY_HIGH;
  GPIO_InitStruct.Alternate = GPIO_AF10_OTG_FS;
  HAL_GPIO_Init(GPIOA, &GPIO_InitStruct);

  /*Configure GPIO pins : SAI2_MCLKA_Pin SAI2_SCKA_Pin SAI2_FSA_Pin SAI2_SDA_Pin */
  GPIO_InitStruct.Pin = SAI2_MCLKA_Pin|SAI2_SCKA_Pin|SAI2_FSA_Pin|SAI2_SDA_Pin;
  GPIO_InitStruct.Mode = GPIO_MODE_AF_PP;
  GPIO_InitStruct.Pull = GPIO_NOPULL;
  GPIO_InitStruct.Speed = GPIO_SPEED_FREQ_LOW;
  GPIO_InitStruct.Alternate = GPIO_AF10_SAI2;
  HAL_GPIO_Init(GPIOI, &GPIO_InitStruct);

  /*Configure GPIO pin : SAI2_SDB_Pin */
  GPIO_InitStruct.Pin = SAI2_SDB_Pin;
  GPIO_InitStruct.Mode = GPIO_MODE_AF_PP;
  GPIO_InitStruct.Pull = GPIO_NOPULL;
  GPIO_InitStruct.Speed = GPIO_SPEED_FREQ_LOW;
  GPIO_InitStruct.Alternate = GPIO_AF10_SAI2;
  HAL_GPIO_Init(SAI2_SDB_GPIO_Port, &GPIO_InitStruct);

  /*Configure GPIO pin : OTG_FS_PowerSwitchOn_Pin */
  GPIO_InitStruct.Pin = OTG_FS_PowerSwitchOn_Pin;
  GPIO_InitStruct.Mode = GPIO_MODE_OUTPUT_PP;
  GPIO_InitStruct.Pull = GPIO_NOPULL;
  GPIO_InitStruct.Speed = GPIO_SPEED_FREQ_LOW;
  HAL_GPIO_Init(OTG_FS_PowerSwitchOn_GPIO_Port, &GPIO_InitStruct);

  /*Configure GPIO pin : DCMI_D5_Pin */
  GPIO_InitStruct.Pin = DCMI_D5_Pin;
  GPIO_InitStruct.Mode = GPIO_MODE_AF_PP;
  GPIO_InitStruct.Pull = GPIO_NOPULL;
  GPIO_InitStruct.Speed = GPIO_SPEED_FREQ_LOW;
  GPIO_InitStruct.Alternate = GPIO_AF13_DCMI;
  HAL_GPIO_Init(DCMI_D5_GPIO_Port, &GPIO_InitStruct);

  /*Configure GPIO pins : ARDUINO_D7_Pin ARDUINO_D8_Pin LCD_DISP_Pin */
  GPIO_InitStruct.Pin = ARDUINO_D7_Pin|ARDUINO_D8_Pin|LCD_DISP_Pin;
  GPIO_InitStruct.Mode = GPIO_MODE_OUTPUT_PP;
  GPIO_InitStruct.Pull = GPIO_NOPULL;
  GPIO_InitStruct.Speed = GPIO_SPEED_FREQ_LOW;
  HAL_GPIO_Init(GPIOI, &GPIO_InitStruct);

  /*Configure GPIO pin : uSD_Detect_Pin */
  GPIO_InitStruct.Pin = uSD_Detect_Pin;
  GPIO_InitStruct.Mode = GPIO_MODE_INPUT;
  GPIO_InitStruct.Pull = GPIO_NOPULL;
  HAL_GPIO_Init(uSD_Detect_GPIO_Port, &GPIO_InitStruct);

  /*Configure GPIO pin : LCD_BL_CTRL_Pin */
  GPIO_InitStruct.Pin = LCD_BL_CTRL_Pin;
  GPIO_InitStruct.Mode = GPIO_MODE_OUTPUT_PP;
  GPIO_InitStruct.Pull = GPIO_NOPULL;
  GPIO_InitStruct.Speed = GPIO_SPEED_FREQ_LOW;
  HAL_GPIO_Init(LCD_BL_CTRL_GPIO_Port, &GPIO_InitStruct);

  /*Configure GPIO pin : DCMI_VSYNC_Pin */
  GPIO_InitStruct.Pin = DCMI_VSYNC_Pin;
  GPIO_InitStruct.Mode = GPIO_MODE_AF_PP;
  GPIO_InitStruct.Pull = GPIO_NOPULL;
  GPIO_InitStruct.Speed = GPIO_SPEED_FREQ_LOW;
  GPIO_InitStruct.Alternate = GPIO_AF13_DCMI;
  HAL_GPIO_Init(DCMI_VSYNC_GPIO_Port, &GPIO_InitStruct);

  /*Configure GPIO pin : OTG_FS_OverCurrent_Pin */
  GPIO_InitStruct.Pin = OTG_FS_OverCurrent_Pin;
  GPIO_InitStruct.Mode = GPIO_MODE_INPUT;
  GPIO_InitStruct.Pull = GPIO_NOPULL;
  HAL_GPIO_Init(OTG_FS_OverCurrent_GPIO_Port, &GPIO_InitStruct);

  /*Configure GPIO pins : TP3_Pin NC2_Pin */
  GPIO_InitStruct.Pin = TP3_Pin|NC2_Pin;
  GPIO_InitStruct.Mode = GPIO_MODE_INPUT;
  GPIO_InitStruct.Pull = GPIO_NOPULL;
  HAL_GPIO_Init(GPIOH, &GPIO_InitStruct);

  /*Configure GPIO pin : ARDUINO_SCK_D13_Pin */
  GPIO_InitStruct.Pin = ARDUINO_SCK_D13_Pin;
  GPIO_InitStruct.Mode = GPIO_MODE_AF_PP;
  GPIO_InitStruct.Pull = GPIO_NOPULL;
  GPIO_InitStruct.Speed = GPIO_SPEED_FREQ_LOW;
  GPIO_InitStruct.Alternate = GPIO_AF5_SPI2;
  HAL_GPIO_Init(ARDUINO_SCK_D13_GPIO_Port, &GPIO_InitStruct);

  /*Configure GPIO pin : DCMI_PWR_EN_Pin */
  GPIO_InitStruct.Pin = DCMI_PWR_EN_Pin;
  GPIO_InitStruct.Mode = GPIO_MODE_OUTPUT_PP;
  GPIO_InitStruct.Pull = GPIO_NOPULL;
  GPIO_InitStruct.Speed = GPIO_SPEED_FREQ_LOW;
  HAL_GPIO_Init(DCMI_PWR_EN_GPIO_Port, &GPIO_InitStruct);

  /*Configure GPIO pins : DCMI_D4_Pin DCMI_D3_Pin DCMI_D0_Pin DCMI_D2_Pin
                           DCMI_D1_Pin */
  GPIO_InitStruct.Pin = DCMI_D4_Pin|DCMI_D3_Pin|DCMI_D0_Pin|DCMI_D2_Pin
                          |DCMI_D1_Pin;
  GPIO_InitStruct.Mode = GPIO_MODE_AF_PP;
  GPIO_InitStruct.Pull = GPIO_NOPULL;
  GPIO_InitStruct.Speed = GPIO_SPEED_FREQ_LOW;
  GPIO_InitStruct.Alternate = GPIO_AF13_DCMI;
  HAL_GPIO_Init(GPIOH, &GPIO_InitStruct);

  /*Configure GPIO pin : ARDUINO_PWM_CS_D5_Pin */
  GPIO_InitStruct.Pin = ARDUINO_PWM_CS_D5_Pin;
  GPIO_InitStruct.Mode = GPIO_MODE_AF_PP;
  GPIO_InitStruct.Pull = GPIO_NOPULL;
  GPIO_InitStruct.Speed = GPIO_SPEED_FREQ_LOW;
  GPIO_InitStruct.Alternate = GPIO_AF2_TIM5;
  HAL_GPIO_Init(ARDUINO_PWM_CS_D5_GPIO_Port, &GPIO_InitStruct);

  /*Configure GPIO pin : ARDUINO_PWM_D10_Pin */
  GPIO_InitStruct.Pin = ARDUINO_PWM_D10_Pin;
  GPIO_InitStruct.Mode = GPIO_MODE_AF_PP;
  GPIO_InitStruct.Pull = GPIO_NOPULL;
  GPIO_InitStruct.Speed = GPIO_SPEED_FREQ_LOW;
  GPIO_InitStruct.Alternate = GPIO_AF1_TIM1;
  HAL_GPIO_Init(ARDUINO_PWM_D10_GPIO_Port, &GPIO_InitStruct);

  /*Configure GPIO pin : LCD_INT_Pin */
  GPIO_InitStruct.Pin = LCD_INT_Pin;
  GPIO_InitStruct.Mode = GPIO_MODE_EVT_RISING;
  GPIO_InitStruct.Pull = GPIO_NOPULL;
  HAL_GPIO_Init(LCD_INT_GPIO_Port, &GPIO_InitStruct);

  /*Configure GPIO pins : ARDUINO_RX_D0_Pin ARDUINO_TX_D1_Pin */
  GPIO_InitStruct.Pin = ARDUINO_RX_D0_Pin|ARDUINO_TX_D1_Pin;
  GPIO_InitStruct.Mode = GPIO_MODE_AF_PP;
  GPIO_InitStruct.Pull = GPIO_NOPULL;
  GPIO_InitStruct.Speed = GPIO_SPEED_FREQ_VERY_HIGH;
  GPIO_InitStruct.Alternate = GPIO_AF8_USART6;
  HAL_GPIO_Init(GPIOC, &GPIO_InitStruct);

  /*Configure GPIO pin : ULPI_NXT_Pin */
  GPIO_InitStruct.Pin = ULPI_NXT_Pin;
  GPIO_InitStruct.Mode = GPIO_MODE_AF_PP;
  GPIO_InitStruct.Pull = GPIO_NOPULL;
  GPIO_InitStruct.Speed = GPIO_SPEED_FREQ_VERY_HIGH;
  GPIO_InitStruct.Alternate = GPIO_AF10_OTG_HS;
  HAL_GPIO_Init(ULPI_NXT_GPIO_Port, &GPIO_InitStruct);

  /*Configure GPIO pins : ARDUINO_D4_Pin ARDUINO_D2_Pin EXT_RST_Pin */
  GPIO_InitStruct.Pin = ARDUINO_D4_Pin|ARDUINO_D2_Pin|EXT_RST_Pin;
  GPIO_InitStruct.Mode = GPIO_MODE_OUTPUT_PP;
  GPIO_InitStruct.Pull = GPIO_NOPULL;
  GPIO_InitStruct.Speed = GPIO_SPEED_FREQ_LOW;
  HAL_GPIO_Init(GPIOG, &GPIO_InitStruct);

  /*Configure GPIO pins : ARDUINO_A4_Pin ARDUINO_A5_Pin ARDUINO_A1_Pin ARDUINO_A2_Pin
                           ARDUINO_A3_Pin */
  GPIO_InitStruct.Pin = ARDUINO_A4_Pin|ARDUINO_A5_Pin|ARDUINO_A1_Pin|ARDUINO_A2_Pin
                          |ARDUINO_A3_Pin;
  GPIO_InitStruct.Mode = GPIO_MODE_ANALOG;
  GPIO_InitStruct.Pull = GPIO_NOPULL;
  HAL_GPIO_Init(GPIOF, &GPIO_InitStruct);

  /*Configure GPIO pins : ULPI_STP_Pin ULPI_DIR_Pin */
  GPIO_InitStruct.Pin = ULPI_STP_Pin|ULPI_DIR_Pin;
  GPIO_InitStruct.Mode = GPIO_MODE_AF_PP;
  GPIO_InitStruct.Pull = GPIO_NOPULL;
  GPIO_InitStruct.Speed = GPIO_SPEED_FREQ_VERY_HIGH;
  GPIO_InitStruct.Alternate = GPIO_AF10_OTG_HS;
  HAL_GPIO_Init(GPIOC, &GPIO_InitStruct);

  /*Configure GPIO pins : RMII_MDC_Pin RMII_RXD0_Pin RMII_RXD1_Pin */
  GPIO_InitStruct.Pin = RMII_MDC_Pin|RMII_RXD0_Pin|RMII_RXD1_Pin;
  GPIO_InitStruct.Mode = GPIO_MODE_AF_PP;
  GPIO_InitStruct.Pull = GPIO_NOPULL;
  GPIO_InitStruct.Speed = GPIO_SPEED_FREQ_VERY_HIGH;
  GPIO_InitStruct.Alternate = GPIO_AF11_ETH;
  HAL_GPIO_Init(GPIOC, &GPIO_InitStruct);

  /*Configure GPIO pin : PB2 */
  GPIO_InitStruct.Pin = GPIO_PIN_2;
  GPIO_InitStruct.Mode = GPIO_MODE_AF_PP;
  GPIO_InitStruct.Pull = GPIO_NOPULL;
  GPIO_InitStruct.Speed = GPIO_SPEED_FREQ_VERY_HIGH;
  GPIO_InitStruct.Alternate = GPIO_AF9_QUADSPI;
  HAL_GPIO_Init(GPIOB, &GPIO_InitStruct);

  /*Configure GPIO pins : QSPI_D1_Pin QSPI_D3_Pin QSPI_D0_Pin */
  GPIO_InitStruct.Pin = QSPI_D1_Pin|QSPI_D3_Pin|QSPI_D0_Pin;
  GPIO_InitStruct.Mode = GPIO_MODE_AF_PP;
  GPIO_InitStruct.Pull = GPIO_NOPULL;
  GPIO_InitStruct.Speed = GPIO_SPEED_FREQ_VERY_HIGH;
  GPIO_InitStruct.Alternate = GPIO_AF9_QUADSPI;
  HAL_GPIO_Init(GPIOD, &GPIO_InitStruct);

  /*Configure GPIO pin : RMII_RXER_Pin */
  GPIO_InitStruct.Pin = RMII_RXER_Pin;
  GPIO_InitStruct.Mode = GPIO_MODE_INPUT;
  GPIO_InitStruct.Pull = GPIO_NOPULL;
  HAL_GPIO_Init(RMII_RXER_GPIO_Port, &GPIO_InitStruct);

  /*Configure GPIO pins : RMII_REF_CLK_Pin RMII_MDIO_Pin RMII_CRS_DV_Pin */
  GPIO_InitStruct.Pin = RMII_REF_CLK_Pin|RMII_MDIO_Pin|RMII_CRS_DV_Pin;
  GPIO_InitStruct.Mode = GPIO_MODE_AF_PP;
  GPIO_InitStruct.Pull = GPIO_NOPULL;
  GPIO_InitStruct.Speed = GPIO_SPEED_FREQ_VERY_HIGH;
  GPIO_InitStruct.Alternate = GPIO_AF11_ETH;
  HAL_GPIO_Init(GPIOA, &GPIO_InitStruct);

  /*Configure GPIO pin : ARDUINO_A0_Pin */
  GPIO_InitStruct.Pin = ARDUINO_A0_Pin;
  GPIO_InitStruct.Mode = GPIO_MODE_ANALOG;
  GPIO_InitStruct.Pull = GPIO_NOPULL;
  HAL_GPIO_Init(ARDUINO_A0_GPIO_Port, &GPIO_InitStruct);

  /*Configure GPIO pins : DCMI_HSYNC_Pin PA6 */
  GPIO_InitStruct.Pin = DCMI_HSYNC_Pin|GPIO_PIN_6;
  GPIO_InitStruct.Mode = GPIO_MODE_AF_PP;
  GPIO_InitStruct.Pull = GPIO_NOPULL;
  GPIO_InitStruct.Speed = GPIO_SPEED_FREQ_LOW;
  GPIO_InitStruct.Alternate = GPIO_AF13_DCMI;
  HAL_GPIO_Init(GPIOA, &GPIO_InitStruct);

  /*Configure GPIO pins : LCD_SCL_Pin LCD_SDA_Pin */
  GPIO_InitStruct.Pin = LCD_SCL_Pin|LCD_SDA_Pin;
  GPIO_InitStruct.Mode = GPIO_MODE_AF_OD;
  GPIO_InitStruct.Pull = GPIO_NOPULL;
  GPIO_InitStruct.Speed = GPIO_SPEED_FREQ_VERY_HIGH;
  GPIO_InitStruct.Alternate = GPIO_AF4_I2C3;
  HAL_GPIO_Init(GPIOH, &GPIO_InitStruct);

  /*Configure GPIO pins : ULPI_CLK_Pin ULPI_D0_Pin */
  GPIO_InitStruct.Pin = ULPI_CLK_Pin|ULPI_D0_Pin;
  GPIO_InitStruct.Mode = GPIO_MODE_AF_PP;
  GPIO_InitStruct.Pull = GPIO_NOPULL;
  GPIO_InitStruct.Speed = GPIO_SPEED_FREQ_VERY_HIGH;
  GPIO_InitStruct.Alternate = GPIO_AF10_OTG_HS;
  HAL_GPIO_Init(GPIOA, &GPIO_InitStruct);

  /*Configure GPIO pin : ARDUINO_PWM_D6_Pin */
  GPIO_InitStruct.Pin = ARDUINO_PWM_D6_Pin;
  GPIO_InitStruct.Mode = GPIO_MODE_AF_PP;
  GPIO_InitStruct.Pull = GPIO_NOPULL;
  GPIO_InitStruct.Speed = GPIO_SPEED_FREQ_LOW;
  GPIO_InitStruct.Alternate = GPIO_AF9_TIM12;
  HAL_GPIO_Init(ARDUINO_PWM_D6_GPIO_Port, &GPIO_InitStruct);

  /*Configure GPIO pins : ARDUINO_MISO_D12_Pin ARDUINO_MOSI_PWM_D11_Pin */
  GPIO_InitStruct.Pin = ARDUINO_MISO_D12_Pin|ARDUINO_MOSI_PWM_D11_Pin;
  GPIO_InitStruct.Mode = GPIO_MODE_AF_PP;
  GPIO_InitStruct.Pull = GPIO_NOPULL;
  GPIO_InitStruct.Speed = GPIO_SPEED_FREQ_LOW;
  GPIO_InitStruct.Alternate = GPIO_AF5_SPI2;
  HAL_GPIO_Init(GPIOB, &GPIO_InitStruct);

}

void StartDefaultTask(void const * argument)
{
  for(;;)
  {
    osDelay(1);
  }
}

void StartTask02(void const * argument)
{
  for(;;)
  {
    osDelay(1);
  }
}

void StartTask03(void const * argument)
{
  for(;;)
  {
    osDelay(1);
  }
}

void StartTask04(void const * argument)
{
  for(;;)
  {
    osDelay(1);
  }
}

void StartTask05(void const * argument)
{
  for(;;)
  {
    osDelay(1);
  }
}

void HAL_TIM_PeriodElapsedCallback(TIM_HandleTypeDef *htim)
{
  if (htim->Instance == TIM1) {
    HAL_IncTick();
  }
}

void Error_Handler(void)
{
  __disable_irq();
  while (1)
  {
  }
}
